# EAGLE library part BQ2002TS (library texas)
CHARGE MANAGEMENT IC

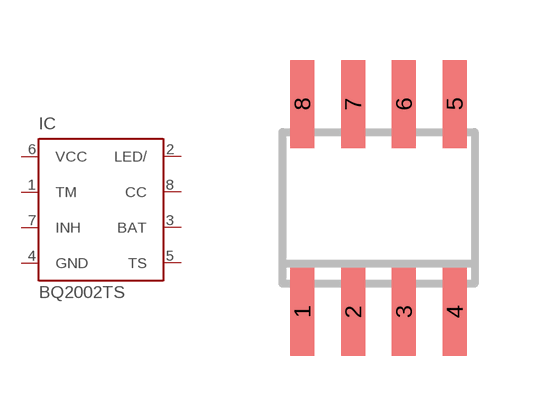
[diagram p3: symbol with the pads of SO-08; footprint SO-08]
Designator prefix IC

## BQ2002TS  [SO-08]
1  TM  in
2  LED/  oc
3  BAT  in
4  GND  pwr
5  TS  in
6  VCC  pwr
7  INH  in
8  CC  oc

## Footprint SO-08 (pad centres in mm)
Small Outline Integrated Circuit
smd 0.6 x 2.2: 1 -1.905,-2.6; 2 -0.635,-2.6; 3 0.635,-2.6; 4 1.905,-2.6; 5 1.905,2.6; 6 0.635,2.6; 7 -0.635,2.6; 8 -1.905,2.6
